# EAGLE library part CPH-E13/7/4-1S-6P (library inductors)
6-pins E13/7/4 coil former (EF12.6) Source: Ferroxcube Ecore.pdf

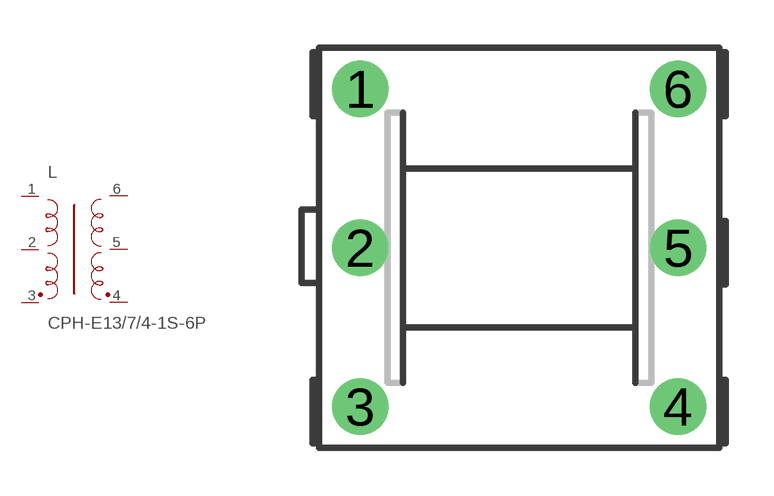
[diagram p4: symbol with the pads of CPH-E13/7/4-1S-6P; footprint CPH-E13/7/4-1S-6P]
Designator prefix L

## CPH-E13/7/4-1S-6P  [CPH-E13/7/4-1S-6P]
1  1  pas
2  2  pas
3  3  pas
4  4  pas
5  5  pas
6  6  pas

## Footprint CPH-E13/7/4-1S-6P (pad centres in mm)
6-pins E13/7/4 coil former (EF12.6) Source: Ferroxcube Ecore.pdf
drill 1.1 pad 1.778 round: 1 -5,5; 2 -5,0; 3 -5,-5; 4 5,-5; 5 5,0; 6 5,5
